VERSION 5.7 ;
  NOWIREEXTENSIONATPIN ON ;
  DIVIDERCHAR "/" ;
  BUSBITCHARS "[]" ;
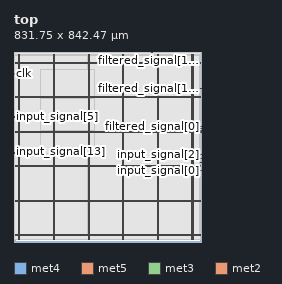
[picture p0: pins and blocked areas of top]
MACRO top
  CLASS BLOCK ;
  FOREIGN top ;
  ORIGIN 0.000 0.000 ;
  SIZE 831.750 BY 842.470 ;
  PIN VGND
    DIRECTION INOUT ;
    USE GROUND ;
    PORT
      LAYER met4 ;
        RECT 24.340 10.640 25.940 829.840 ;
    END
    PORT
      LAYER met4 ;
        RECT 177.940 10.640 179.540 829.840 ;
    END
    PORT
      LAYER met4 ;
        RECT 331.540 10.640 333.140 829.840 ;
    END
    PORT
      LAYER met4 ;
        RECT 485.140 10.640 486.740 829.840 ;
    END
    PORT
      LAYER met4 ;
        RECT 638.740 10.640 640.340 829.840 ;
    END
    PORT
      LAYER met4 ;
        RECT 792.340 10.640 793.940 829.840 ;
    END
    PORT
      LAYER met5 ;
        RECT 5.280 30.030 826.400 31.630 ;
    END
    PORT
      LAYER met5 ;
        RECT 5.280 183.210 826.400 184.810 ;
    END
    PORT
      LAYER met5 ;
        RECT 5.280 336.390 826.400 337.990 ;
    END
    PORT
      LAYER met5 ;
        RECT 5.280 489.570 826.400 491.170 ;
    END
    PORT
      LAYER met5 ;
        RECT 5.280 642.750 826.400 644.350 ;
    END
    PORT
      LAYER met5 ;
        RECT 5.280 795.930 826.400 797.530 ;
    END
  END VGND
  PIN VPWR
    DIRECTION INOUT ;
    USE POWER ;
    PORT
      LAYER met4 ;
        RECT 21.040 10.640 22.640 829.840 ;
    END
    PORT
      LAYER met4 ;
        RECT 174.640 10.640 176.240 829.840 ;
    END
    PORT
      LAYER met4 ;
        RECT 328.240 10.640 329.840 829.840 ;
    END
    PORT
      LAYER met4 ;
        RECT 481.840 10.640 483.440 829.840 ;
    END
    PORT
      LAYER met4 ;
        RECT 635.440 10.640 637.040 829.840 ;
    END
    PORT
      LAYER met4 ;
        RECT 789.040 10.640 790.640 829.840 ;
    END
    PORT
      LAYER met5 ;
        RECT 5.280 26.730 826.400 28.330 ;
    END
    PORT
      LAYER met5 ;
        RECT 5.280 179.910 826.400 181.510 ;
    END
    PORT
      LAYER met5 ;
        RECT 5.280 333.090 826.400 334.690 ;
    END
    PORT
      LAYER met5 ;
        RECT 5.280 486.270 826.400 487.870 ;
    END
    PORT
      LAYER met5 ;
        RECT 5.280 639.450 826.400 641.050 ;
    END
    PORT
      LAYER met5 ;
        RECT 5.280 792.630 826.400 794.230 ;
    END
  END VPWR
  PIN clk
    DIRECTION INPUT ;
    USE SIGNAL ;
    ANTENNAGATEAREA 0.852000 ;
    ANTENNADIFFAREA 0.434700 ;
    PORT
      LAYER met3 ;
        RECT 0.000 748.040 4.000 748.640 ;
    END
  END clk
  PIN filtered_signal[0]
    DIRECTION OUTPUT ;
    USE SIGNAL ;
    ANTENNADIFFAREA 0.795200 ;
    PORT
      LAYER met3 ;
        RECT 827.750 510.040 831.750 510.640 ;
    END
  END filtered_signal[0]
  PIN filtered_signal[10]
    DIRECTION OUTPUT ;
    USE SIGNAL ;
    ANTENNADIFFAREA 0.795200 ;
    PORT
      LAYER met2 ;
        RECT 608.670 838.470 608.950 842.470 ;
    END
  END filtered_signal[10]
  PIN filtered_signal[11]
    DIRECTION OUTPUT ;
    USE SIGNAL ;
    ANTENNADIFFAREA 0.795200 ;
    PORT
      LAYER met2 ;
        RECT 615.110 838.470 615.390 842.470 ;
    END
  END filtered_signal[11]
  PIN filtered_signal[12]
    DIRECTION OUTPUT ;
    USE SIGNAL ;
    ANTENNADIFFAREA 0.795200 ;
    PORT
      LAYER met2 ;
        RECT 624.770 838.470 625.050 842.470 ;
    END
  END filtered_signal[12]
  PIN filtered_signal[13]
    DIRECTION OUTPUT ;
    USE SIGNAL ;
    ANTENNADIFFAREA 0.795200 ;
    PORT
      LAYER met2 ;
        RECT 627.990 838.470 628.270 842.470 ;
    END
  END filtered_signal[13]
  PIN filtered_signal[14]
    DIRECTION OUTPUT ;
    USE SIGNAL ;
    ANTENNADIFFAREA 0.795200 ;
    PORT
      LAYER met2 ;
        RECT 621.550 838.470 621.830 842.470 ;
    END
  END filtered_signal[14]
  PIN filtered_signal[15]
    DIRECTION OUTPUT ;
    USE SIGNAL ;
    ANTENNADIFFAREA 0.445500 ;
    PORT
      LAYER met3 ;
        RECT 827.750 680.040 831.750 680.640 ;
    END
  END filtered_signal[15]
  PIN filtered_signal[1]
    DIRECTION OUTPUT ;
    USE SIGNAL ;
    ANTENNADIFFAREA 0.795200 ;
    PORT
      LAYER met3 ;
        RECT 827.750 503.240 831.750 503.840 ;
    END
  END filtered_signal[1]
  PIN filtered_signal[2]
    DIRECTION OUTPUT ;
    USE SIGNAL ;
    ANTENNADIFFAREA 0.445500 ;
    PORT
      LAYER met3 ;
        RECT 827.750 493.040 831.750 493.640 ;
    END
  END filtered_signal[2]
  PIN filtered_signal[3]
    DIRECTION OUTPUT ;
    USE SIGNAL ;
    ANTENNADIFFAREA 0.445500 ;
    PORT
      LAYER met3 ;
        RECT 827.750 486.240 831.750 486.840 ;
    END
  END filtered_signal[3]
  PIN filtered_signal[4]
    DIRECTION OUTPUT ;
    USE SIGNAL ;
    ANTENNADIFFAREA 0.795200 ;
    PORT
      LAYER met2 ;
        RECT 576.470 838.470 576.750 842.470 ;
    END
  END filtered_signal[4]
  PIN filtered_signal[5]
    DIRECTION OUTPUT ;
    USE SIGNAL ;
    ANTENNADIFFAREA 0.795200 ;
    PORT
      LAYER met3 ;
        RECT 827.750 489.640 831.750 490.240 ;
    END
  END filtered_signal[5]
  PIN filtered_signal[6]
    DIRECTION OUTPUT ;
    USE SIGNAL ;
    ANTENNADIFFAREA 0.795200 ;
    PORT
      LAYER met2 ;
        RECT 586.130 838.470 586.410 842.470 ;
    END
  END filtered_signal[6]
  PIN filtered_signal[7]
    DIRECTION OUTPUT ;
    USE SIGNAL ;
    ANTENNADIFFAREA 0.795200 ;
    PORT
      LAYER met2 ;
        RECT 599.010 838.470 599.290 842.470 ;
    END
  END filtered_signal[7]
  PIN filtered_signal[8]
    DIRECTION OUTPUT ;
    USE SIGNAL ;
    ANTENNADIFFAREA 0.795200 ;
    PORT
      LAYER met2 ;
        RECT 611.890 838.470 612.170 842.470 ;
    END
  END filtered_signal[8]
  PIN filtered_signal[9]
    DIRECTION OUTPUT ;
    USE SIGNAL ;
    ANTENNADIFFAREA 0.795200 ;
    PORT
      LAYER met2 ;
        RECT 595.790 838.470 596.070 842.470 ;
    END
  END filtered_signal[9]
  PIN input_signal[0]
    DIRECTION INPUT ;
    USE SIGNAL ;
    ANTENNAGATEAREA 0.159000 ;
    PORT
      LAYER met3 ;
        RECT 827.750 316.240 831.750 316.840 ;
    END
  END input_signal[0]
  PIN input_signal[10]
    DIRECTION INPUT ;
    USE SIGNAL ;
    ANTENNAGATEAREA 0.196500 ;
    PORT
      LAYER met3 ;
        RECT 0.000 411.440 4.000 412.040 ;
    END
  END input_signal[10]
  PIN input_signal[11]
    DIRECTION INPUT ;
    USE SIGNAL ;
    ANTENNAGATEAREA 0.196500 ;
    PORT
      LAYER met3 ;
        RECT 0.000 397.840 4.000 398.440 ;
    END
  END input_signal[11]
  PIN input_signal[12]
    DIRECTION INPUT ;
    USE SIGNAL ;
    ANTENNAGATEAREA 0.196500 ;
    PORT
      LAYER met3 ;
        RECT 0.000 394.440 4.000 395.040 ;
    END
  END input_signal[12]
  PIN input_signal[13]
    DIRECTION INPUT ;
    USE SIGNAL ;
    ANTENNAGATEAREA 0.196500 ;
    PORT
      LAYER met3 ;
        RECT 0.000 401.240 4.000 401.840 ;
    END
  END input_signal[13]
  PIN input_signal[14]
    DIRECTION INPUT ;
    USE SIGNAL ;
    ANTENNAGATEAREA 0.196500 ;
    PORT
      LAYER met3 ;
        RECT 0.000 408.040 4.000 408.640 ;
    END
  END input_signal[14]
  PIN input_signal[15]
    DIRECTION INPUT ;
    USE SIGNAL ;
    ANTENNAGATEAREA 0.196500 ;
    PORT
      LAYER met3 ;
        RECT 0.000 659.640 4.000 660.240 ;
    END
  END input_signal[15]
  PIN input_signal[1]
    DIRECTION INPUT ;
    USE SIGNAL ;
    ANTENNAGATEAREA 0.196500 ;
    PORT
      LAYER met2 ;
        RECT 492.750 838.470 493.030 842.470 ;
    END
  END input_signal[1]
  PIN input_signal[2]
    DIRECTION INPUT ;
    USE SIGNAL ;
    ANTENNAGATEAREA 0.159000 ;
    PORT
      LAYER met3 ;
        RECT 827.750 353.640 831.750 354.240 ;
    END
  END input_signal[2]
  PIN input_signal[3]
    DIRECTION INPUT ;
    USE SIGNAL ;
    ANTENNAGATEAREA 0.213000 ;
    PORT
      LAYER met3 ;
        RECT 827.750 387.640 831.750 388.240 ;
    END
  END input_signal[3]
  PIN input_signal[4]
    DIRECTION INPUT ;
    USE SIGNAL ;
    ANTENNAGATEAREA 0.213000 ;
    PORT
      LAYER met3 ;
        RECT 827.750 370.640 831.750 371.240 ;
    END
  END input_signal[4]
  PIN input_signal[5]
    DIRECTION INPUT ;
    USE SIGNAL ;
    ANTENNAGATEAREA 0.196500 ;
    PORT
      LAYER met3 ;
        RECT 0.000 554.240 4.000 554.840 ;
    END
  END input_signal[5]
  PIN input_signal[6]
    DIRECTION INPUT ;
    USE SIGNAL ;
    ANTENNAGATEAREA 0.196500 ;
    PORT
      LAYER met3 ;
        RECT 0.000 404.640 4.000 405.240 ;
    END
  END input_signal[6]
  PIN input_signal[7]
    DIRECTION INPUT ;
    USE SIGNAL ;
    ANTENNAGATEAREA 0.196500 ;
    PORT
      LAYER met3 ;
        RECT 0.000 384.240 4.000 384.840 ;
    END
  END input_signal[7]
  PIN input_signal[8]
    DIRECTION INPUT ;
    USE SIGNAL ;
    ANTENNAGATEAREA 0.196500 ;
    PORT
      LAYER met3 ;
        RECT 0.000 387.640 4.000 388.240 ;
    END
  END input_signal[8]
  PIN input_signal[9]
    DIRECTION INPUT ;
    USE SIGNAL ;
    ANTENNAGATEAREA 0.196500 ;
    PORT
      LAYER met3 ;
        RECT 0.000 414.840 4.000 415.440 ;
    END
  END input_signal[9]
  PIN rst
    DIRECTION INPUT ;
    USE SIGNAL ;
    ANTENNAGATEAREA 0.196500 ;
    PORT
      LAYER met3 ;
        RECT 0.000 744.640 4.000 745.240 ;
    END
  END rst
  PIN tap[0]
    DIRECTION INPUT ;
    USE SIGNAL ;
    ANTENNAGATEAREA 0.247500 ;
    PORT
      LAYER met2 ;
        RECT 602.230 838.470 602.510 842.470 ;
    END
  END tap[0]
  PIN tap[1]
    DIRECTION INPUT ;
    USE SIGNAL ;
    ANTENNAGATEAREA 0.213000 ;
    PORT
      LAYER met2 ;
        RECT 618.330 838.470 618.610 842.470 ;
    END
  END tap[1]
  PIN tap[2]
    DIRECTION INPUT ;
    USE SIGNAL ;
    ANTENNAGATEAREA 0.247500 ;
    PORT
      LAYER met2 ;
        RECT 566.810 838.470 567.090 842.470 ;
    END
  END tap[2]
  PIN tap[3]
    DIRECTION INPUT ;
    USE SIGNAL ;
    ANTENNAGATEAREA 0.247500 ;
    PORT
      LAYER met2 ;
        RECT 563.590 838.470 563.870 842.470 ;
    END
  END tap[3]
  OBS
      LAYER li1 ;
        RECT 5.520 10.795 826.160 829.685 ;
      LAYER met1 ;
        RECT 3.750 10.640 826.550 829.840 ;
      LAYER met2 ;
        RECT 3.770 838.190 492.470 838.470 ;
        RECT 493.310 838.190 563.310 838.470 ;
        RECT 564.150 838.190 566.530 838.470 ;
        RECT 567.370 838.190 576.190 838.470 ;
        RECT 577.030 838.190 585.850 838.470 ;
        RECT 586.690 838.190 595.510 838.470 ;
        RECT 596.350 838.190 598.730 838.470 ;
        RECT 599.570 838.190 601.950 838.470 ;
        RECT 602.790 838.190 608.390 838.470 ;
        RECT 609.230 838.190 611.610 838.470 ;
        RECT 612.450 838.190 614.830 838.470 ;
        RECT 615.670 838.190 618.050 838.470 ;
        RECT 618.890 838.190 621.270 838.470 ;
        RECT 622.110 838.190 624.490 838.470 ;
        RECT 625.330 838.190 627.710 838.470 ;
        RECT 628.550 838.190 826.530 838.470 ;
        RECT 3.770 10.695 826.530 838.190 ;
      LAYER met3 ;
        RECT 3.745 749.040 827.750 829.765 ;
        RECT 4.400 747.640 827.750 749.040 ;
        RECT 3.745 745.640 827.750 747.640 ;
        RECT 4.400 744.240 827.750 745.640 ;
        RECT 3.745 681.040 827.750 744.240 ;
        RECT 3.745 679.640 827.350 681.040 ;
        RECT 3.745 660.640 827.750 679.640 ;
        RECT 4.400 659.240 827.750 660.640 ;
        RECT 3.745 555.240 827.750 659.240 ;
        RECT 4.400 553.840 827.750 555.240 ;
        RECT 3.745 511.040 827.750 553.840 ;
        RECT 3.745 509.640 827.350 511.040 ;
        RECT 3.745 504.240 827.750 509.640 ;
        RECT 3.745 502.840 827.350 504.240 ;
        RECT 3.745 494.040 827.750 502.840 ;
        RECT 3.745 492.640 827.350 494.040 ;
        RECT 3.745 490.640 827.750 492.640 ;
        RECT 3.745 489.240 827.350 490.640 ;
        RECT 3.745 487.240 827.750 489.240 ;
        RECT 3.745 485.840 827.350 487.240 ;
        RECT 3.745 415.840 827.750 485.840 ;
        RECT 4.400 414.440 827.750 415.840 ;
        RECT 3.745 412.440 827.750 414.440 ;
        RECT 4.400 411.040 827.750 412.440 ;
        RECT 3.745 409.040 827.750 411.040 ;
        RECT 4.400 407.640 827.750 409.040 ;
        RECT 3.745 405.640 827.750 407.640 ;
        RECT 4.400 404.240 827.750 405.640 ;
        RECT 3.745 402.240 827.750 404.240 ;
        RECT 4.400 400.840 827.750 402.240 ;
        RECT 3.745 398.840 827.750 400.840 ;
        RECT 4.400 397.440 827.750 398.840 ;
        RECT 3.745 395.440 827.750 397.440 ;
        RECT 4.400 394.040 827.750 395.440 ;
        RECT 3.745 388.640 827.750 394.040 ;
        RECT 4.400 387.240 827.350 388.640 ;
        RECT 3.745 385.240 827.750 387.240 ;
        RECT 4.400 383.840 827.750 385.240 ;
        RECT 3.745 371.640 827.750 383.840 ;
        RECT 3.745 370.240 827.350 371.640 ;
        RECT 3.745 354.640 827.750 370.240 ;
        RECT 3.745 353.240 827.350 354.640 ;
        RECT 3.745 317.240 827.750 353.240 ;
        RECT 3.745 315.840 827.350 317.240 ;
        RECT 3.745 10.715 827.750 315.840 ;
      LAYER met4 ;
        RECT 3.975 28.055 20.640 828.745 ;
        RECT 23.040 28.055 23.940 828.745 ;
        RECT 26.340 28.055 174.240 828.745 ;
        RECT 176.640 28.055 177.540 828.745 ;
        RECT 179.940 28.055 327.840 828.745 ;
        RECT 330.240 28.055 331.140 828.745 ;
        RECT 333.540 28.055 481.440 828.745 ;
        RECT 483.840 28.055 484.740 828.745 ;
        RECT 487.140 28.055 635.040 828.745 ;
        RECT 637.440 28.055 638.340 828.745 ;
        RECT 640.740 28.055 788.640 828.745 ;
        RECT 791.040 28.055 791.940 828.745 ;
        RECT 794.340 28.055 820.345 828.745 ;
      LAYER met5 ;
        RECT 117.420 645.950 359.140 764.100 ;
        RECT 117.420 492.770 359.140 637.850 ;
        RECT 117.420 391.900 359.140 484.670 ;
  END
END top
END LIBRARY

